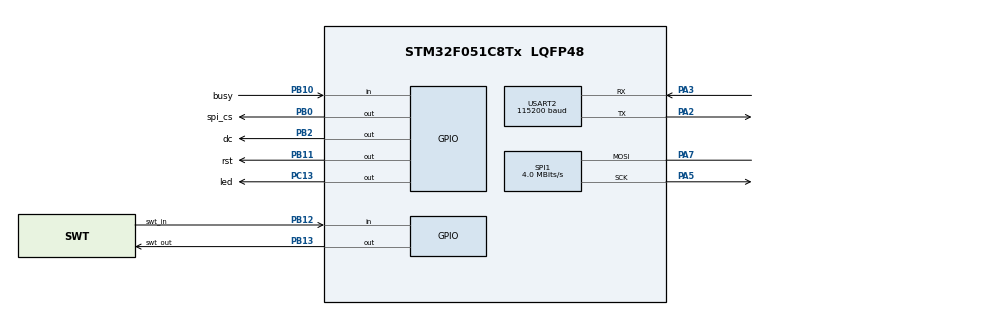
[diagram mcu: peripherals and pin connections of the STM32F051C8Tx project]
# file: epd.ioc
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Mcu.Family=STM32F0
Mcu.Name=STM32F051C8Tx
Mcu.Package=LQFP48
NVIC.RTC_IRQn=true\:0\:0\:false\:false\:true\:true
NVIC.USART2_IRQn=true\:0\:0\:false\:false\:true\:true
PA13.Mode=Serial_Wire
PA13.Signal=SYS_SWDIO
PA14.Mode=Serial_Wire
PA14.Signal=SYS_SWCLK
PA2.Mode=Asynchronous
PA2.Signal=USART2_TX
PA3.Mode=Asynchronous
PA3.Signal=USART2_RX
PA5.Mode=Simplex_Bidirectional_Master
PA5.Signal=SPI1_SCK
PA7.Mode=Simplex_Bidirectional_Master
PA7.Signal=SPI1_MOSI
PB0.GPIO_Label=spi_cs
PB0.Signal=GPIO_Output
PB10.GPIO_Label=busy
PB10.Signal=GPIO_Input
PB11.GPIO_Label=rst
PB11.Signal=GPIO_Output
PB12.GPIO_Label=swt_in
PB12.Signal=GPIO_Input
PB13.GPIO_Label=swt_out
PB13.Signal=GPIO_Output
PB2.GPIO_Label=dc
PB2.Signal=GPIO_Output
PC13.GPIO_Label=led
PC13.Signal=GPIO_Output
PC14-OSC32_IN.Mode=LSE-External-Oscillator
PC14-OSC32_IN.Signal=RCC_OSC32_IN
PC15-OSC32_OUT.Mode=LSE-External-Oscillator
PC15-OSC32_OUT.Signal=RCC_OSC32_OUT
PF0-OSC_IN.Mode=HSE-External-Oscillator
PF0-OSC_IN.Signal=RCC_OSC_IN
PF1-OSC_OUT.Mode=HSE-External-Oscillator
PF1-OSC_OUT.Signal=RCC_OSC_OUT
ProjectManager.HeapSize=0x200
ProjectManager.StackSize=0x400
ProjectManager.TargetToolchain=Makefile
RCC.AHBFreq_Value=16000000
RCC.APB1Freq_Value=16000000
RCC.APB1TimFreq_Value=16000000
RCC.HCLKFreq_Value=16000000
RCC.PLLSourceVirtual=RCC_PLLSOURCE_HSE
RCC.RTCClockSelection=RCC_RTCCLKSOURCE_LSE
RCC.SYSCLKFreq_VALUE=16000000
RCC.SYSCLKSource=RCC_SYSCLKSOURCE_PLLCLK
RTC.Alarm-Alarm\ A=RTC_ALARM_A
RTC.AlarmMaskDateWeekDay-Alarm\ A=RTC_ALARMMASK_DATEWEEKDAY
RTC.AlarmMaskHours-Alarm\ A=RTC_ALARMMASK_HOURS
RTC.AlarmMaskMinutes-Alarm\ A=RTC_ALARMMASK_MINUTES
RTC.AlarmSubSecondMask-Alarm\ A=RTC_ALARMSUBSECONDMASK_ALL
SPI1.BaudRatePrescaler=SPI_BAUDRATEPRESCALER_4
SPI1.CalculateBaudRate=4.0 MBits/s
SPI1.DataSize=SPI_DATASIZE_8BIT
SPI1.Direction=SPI_DIRECTION_1LINE
SPI1.Mode=SPI_MODE_MASTER
SPI1.VirtualType=VM_MASTER
USART2.BaudRate=115200
USART2.VirtualMode-Asynchronous=VM_ASYNC
VP_RTC_VS_RTC_Activate.Mode=RTC_Enabled
VP_RTC_VS_RTC_Alarm_A_Intern.Mode=Alarm A
VP_RTC_VS_RTC_Calendar.Mode=RTC_Calendar
board=epd

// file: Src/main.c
/**
  ******************************************************************************
  * @file           : main.c
  * @brief          : Main program body
  ******************************************************************************
  ** This notice applies to any and all portions of this file
  * that are not between comment pairs USER CODE BEGIN and
  * USER CODE END. Other portions of this file, whether
  * inserted by the user or by software development tools
  * are owned by their respective copyright owners.
  *
  * COPYRIGHT(c) 2018 STMicroelectronics
  *
  * Redistribution and use in source and binary forms, with or without modification,
  * are permitted provided that the following conditions are met:
  *   1. Redistributions of source code must retain the above copyright notice,
  *      this list of conditions and the following disclaimer.
  *   2. Redistributions in binary form must reproduce the above copyright notice,
  *      this list of conditions and the following disclaimer in the documentation
  *      and/or other materials provided with the distribution.
  *   3. Neither the name of STMicroelectronics nor the names of its contributors
  *      may be used to endorse or promote products derived from this software
  *      without specific prior written permission.
  *
  * THIS SOFTWARE IS PROVIDED BY THE COPYRIGHT HOLDERS AND CONTRIBUTORS "AS IS"
  * AND ANY EXPRESS OR IMPLIED WARRANTIES, INCLUDING, BUT NOT LIMITED TO, THE
  * IMPLIED WARRANTIES OF MERCHANTABILITY AND FITNESS FOR A PARTICULAR PURPOSE ARE
  * DISCLAIMED. IN NO EVENT SHALL THE COPYRIGHT HOLDER OR CONTRIBUTORS BE LIABLE
  * FOR ANY DIRECT, INDIRECT, INCIDENTAL, SPECIAL, EXEMPLARY, OR CONSEQUENTIAL
  * DAMAGES (INCLUDING, BUT NOT LIMITED TO, PROCUREMENT OF SUBSTITUTE GOODS OR
  * SERVICES; LOSS OF USE, DATA, OR PROFITS; OR BUSINESS INTERRUPTION) HOWEVER
  * CAUSED AND ON ANY THEORY OF LIABILITY, WHETHER IN CONTRACT, STRICT LIABILITY,
  * OR TORT (INCLUDING NEGLIGENCE OR OTHERWISE) ARISING IN ANY WAY OUT OF THE USE
  * OF THIS SOFTWARE, EVEN IF ADVISED OF THE POSSIBILITY OF SUCH DAMAGE.
  *
  ******************************************************************************
  */
#include "main.h"
#include "stm32f0xx_hal.h"

/* USER CODE BEGIN Includes */
#include "epd2in9.h"
#include "epdif.h"
#include "epdpaint.h"
#include "bitmaps.h"
#include <stdlib.h>

/* USER CODE END Includes */

RTC_HandleTypeDef hrtc;

SPI_HandleTypeDef hspi1;

UART_HandleTypeDef huart2;

/* USER CODE BEGIN PV */
/* Private variables ---------------------------------------------------------*/
#define COLORED      0
#define UNCOLORED    1
/* After this many RTC-alarm wakeups without any UART activity, fall back
   from SLEEP (UART debug) mode to the low-power STOP mode. */
#define UART_IDLE_TIMEOUT_MIN  5

int uart_state = 0;
uint8_t rxBuf[12];
uint32_t uart_idle_min = 0;         /* consecutive alarm wakeups w/o UART traffic */
volatile uint8_t rtc_alarm_flag = 0; /* set in HAL_RTC_AlarmAEventCallback */

/* USER CODE END PV */

void SystemClock_Config(void);
static void MX_GPIO_Init(void);
static void MX_RTC_Init(void);
static void MX_SPI1_Init(void);
static void MX_USART2_UART_Init(void);
static void MY_GPIO_DeInit(void);

/* USER CODE BEGIN PFP */
/* Private function prototypes -----------------------------------------------*/

/* USER CODE END PFP */

/* USER CODE BEGIN 0 */
void HAL_UART_RxCpltCallback(UART_HandleTypeDef *UartHandle)
{
    uart_idle_min = 0;   /* any UART traffic resets the idle timeout */
    /* Zero-initialize: HAL_RTC_SetTime() ORs DayLightSaving/StoreOperation
       into RTC->CR, so stack garbage here could set CR.FMT (12-hour mode),
       disable Alarm A, or trigger a DST hour shift. */
    RTC_TimeTypeDef st = {0};
    RTC_DateTypeDef sd = {0};
    switch (uart_state) {
        case 0:
            HAL_UART_Transmit_IT(UartHandle, (uint8_t *)"\r\nInput Date(yy-mm-dd:w):\r\n", 27);
            HAL_UART_Receive_IT(UartHandle, rxBuf, 10);
            uart_state = 1;
            break;
        case 1:
            sd.Year = (rxBuf[0] - '0') * 10 + rxBuf[1] - '0';
            sd.Month = (rxBuf[3] - '0') * 10 + rxBuf[4] - '0';
            sd.Date = (rxBuf[6] - '0') * 10 + rxBuf[7] - '0';
            sd.WeekDay = rxBuf[9] - '0';
            HAL_RTC_SetDate(&hrtc, &sd, RTC_FORMAT_BIN);
            HAL_UART_Transmit_IT(UartHandle, (uint8_t *)"\r\nInput Time(hh:mm:ss):\r\n", 25);
            HAL_UART_Receive_IT(UartHandle, rxBuf, 8);
            uart_state = 2;
            break;
        case 2:
            st.Hours = (rxBuf[0] - '0') * 10 + rxBuf[1] - '0';
            st.Minutes = (rxBuf[3] - '0') * 10 + rxBuf[4] - '0';
            st.Seconds = (rxBuf[6] - '0') * 10 + rxBuf[7] - '0';
            st.TimeFormat = RTC_HOURFORMAT_24;
            /* USE_FULL_ASSERT is off, so the HAL would silently write an
               invalid hour (e.g. 15 into a 12-hour-mode RTC) and let the
               hour counter run past 23.  Validate before writing. */
            if ((st.Hours > 23) || (st.Minutes > 59) || (st.Seconds > 59)) {
                HAL_UART_Transmit_IT(UartHandle, (uint8_t *)"\r\nBad Time, Input Again(hh:mm:ss):\r\n", 34);
                HAL_UART_Receive_IT(UartHandle, rxBuf, 8);
                break;   /* stay in state 2 and retry */
            }
            if (HAL_RTC_SetTime(&hrtc, &st, RTC_FORMAT_BIN) != HAL_OK) {
                HAL_UART_Transmit_IT(UartHandle, (uint8_t *)"\r\nRTC Set Time Failed!\r\n", 24);
                HAL_UART_Receive_IT(UartHandle, rxBuf, 1);
                uart_state = 3;
                break;
            }
            HAL_UART_Transmit_IT(UartHandle, (uint8_t *)"\r\nInput Done!\r\n", 15);
            HAL_UART_Receive_IT(UartHandle, rxBuf, 1);
            uart_state = 3;
            break;
    }

}

void HAL_RTC_AlarmAEventCallback(RTC_HandleTypeDef *hrtc)
{
    rtc_alarm_flag = 1;  /* remember that the RTC alarm woke the MCU */
//    HAL_GPIO_TogglePin(led_GPIO_Port, led_Pin);
}
/* USER CODE END 0 */

int main(void)
{
  /* USER CODE BEGIN 1 */
  unsigned char* frame_buffer = (unsigned char*)malloc(EPD_WIDTH * EPD_HEIGHT / 8);

  /* USER CODE END 1 */

  /* MCU Configuration----------------------------------------------------------*/

  /* Reset of all peripherals, Initializes the Flash interface and the Systick. */
  HAL_Init();

  /* Configure the system clock */
  SystemClock_Config();

  /* Initialize all configured peripherals */
  MX_GPIO_Init();
  MX_RTC_Init();
  MX_SPI1_Init();
  MX_USART2_UART_Init();
  /* USER CODE BEGIN 2 */
  EPD epd;
  if (EPD_Init(&epd, lut_full_update) != 0) {
    printf("e-Paper init failed\n");
    return -1;
  }

  Paint paint;
  Paint_Init(&paint, frame_buffer, epd.width, epd.height);
  Paint_Clear(&paint, UNCOLORED);
  Paint_SetRotate(&paint, ROTATE_90);

  Paint_DrawStringAt(&paint, 20, 50, "Simple Calendar.", &Font24, COLORED);
  EPD_SetFrameMemory(&epd, frame_buffer, 0, 0, Paint_GetWidth(&paint), Paint_GetHeight(&paint));
  EPD_DisplayFrame(&epd);

  Paint_Clear(&paint, UNCOLORED);

  /* USER CODE END 2 */

  /* Infinite loop */
  /* USER CODE BEGIN WHILE */
  HAL_GPIO_WritePin(led_GPIO_Port, led_Pin, GPIO_PIN_SET);
  int swton = 1;
  HAL_GPIO_WritePin(swt_out_GPIO_Port, swt_out_Pin, GPIO_PIN_SET);
  if (HAL_GPIO_ReadPin(swt_in_GPIO_Port, swt_in_Pin) != GPIO_PIN_SET) swton = 0;
  HAL_GPIO_WritePin(swt_out_GPIO_Port, swt_out_Pin, GPIO_PIN_RESET);
  if (HAL_GPIO_ReadPin(swt_in_GPIO_Port, swt_in_Pin) != GPIO_PIN_RESET) swton = 0;
  if (swton)
      HAL_UART_Receive_IT(&huart2, rxBuf, 1);
  else {
      MY_GPIO_DeInit();
  }
  while (1)
  {
      RTC_TimeTypeDef st;
      RTC_DateTypeDef sd;
      char date[10];
      const char* wkd[] = {"Mon", "Tue", "Wen", "Thu", "Fri", "Sat", "Sun"};

      /* Read the RTC current time first.  After every low-power wakeup the
         calendar shadow registers must be re-synchronized with the APB clock
         domain (clear RSF, wait until it is set again) before reading, or the
         read can return torn values; the HAL documents this as mandatory
         after wakeup from low-power modes. */
      if (HAL_RTC_WaitForSynchro(&hrtc) != HAL_OK) {
        printf("RTC sync failed\n");
      }
      HAL_RTC_GetTime(&hrtc, &st, RTC_FORMAT_BIN);
      HAL_RTC_GetDate(&hrtc, &sd, RTC_FORMAT_BIN);

      /* Once a day (00:00) do a full refresh to clear partial-update
         ghosting, as required by the vendor after many partial refreshes.
         The old approach reset the MCU at exactly 00:00:00; that collided
         with the calendar's day rollover and could corrupt the hour field
         (hours kept counting past 23 while the date never advanced).  A
         plain full refresh here never touches the RTC at the rollover
         instant, so the calendar cannot be disturbed. */
      int full_refresh = (st.Hours == 0) && (st.Minutes == 0);

      /* Wake the e-Paper from deep sleep (EPD_Sleep is called at the end of
         the previous loop iteration). Deep sleep keeps its standby current
         near zero, but a full re-init is required before the next refresh. */
      if (EPD_Init(&epd, full_refresh ? lut_full_update : lut_partial_update) != 0) {
        printf("e-Paper init failed\n");
        return -1;
      }

      /* Write strings to the buffer */
      HAL_GPIO_WritePin(led_GPIO_Port, led_Pin, GPIO_PIN_RESET);
      Paint_DrawFilledRectangle(&paint, 50, 0, 290, 24, UNCOLORED);
      Paint_DrawFilledRectangle(&paint, 0, 120, 296, 127, UNCOLORED);
      sprintf(date, "%02d-%02d-%02d", sd.Year, sd.Month, sd.Date);
      Paint_DrawStringAt(&paint, 50, 0, date, &Font24, COLORED);
      Paint_DrawStringAt(&paint, 200, 0, wkd[sd.WeekDay - 1], &Font24, COLORED);
      Paint_DrawBitmap(&paint, 0, 28, 9, 85, digits[st.Hours / 10]);
      Paint_DrawBitmap(&paint, 70, 28, 9, 85, digits[st.Hours % 10]);
      Paint_DrawBitmap(&paint, 10 + 70 * 2, 28, 9, 85, digits[st.Minutes / 10]);
      Paint_DrawBitmap(&paint, 10 + 70 * 3, 28, 9, 85, digits[st.Minutes % 10]);
      Paint_DrawBitmap(&paint, 135, 55, 2, 13, point);
      Paint_DrawBitmap(&paint, 135, 85, 2, 13, point);
      HAL_GPIO_WritePin(led_GPIO_Port, led_Pin, GPIO_PIN_SET);
      /* Display the frame_buffer (single refresh; the duplicated one was
         removed to halve the refresh energy) */
      EPD_SetFrameMemory(&epd, frame_buffer, 0, 0, Paint_GetWidth(&paint), Paint_GetHeight(&paint));
      EPD_DisplayFrame(&epd);
      /* Deep sleep the e-Paper to cut its standby current */
      EPD_Sleep(&epd);

      if (swton) {
          /* UART/time-setting mode: count RTC-alarm wakeups. If no UART
             traffic arrives for UART_IDLE_TIMEOUT_MIN minutes, switch to
             STOP mode (lowest MCU idle current). */
          if (rtc_alarm_flag) {
              rtc_alarm_flag = 0;
              if (++uart_idle_min >= UART_IDLE_TIMEOUT_MIN) {
                  swton = 0;
                  MY_GPIO_DeInit();
              }
          }
          HAL_SuspendTick();
          HAL_PWR_EnterSLEEPMode(PWR_MAINREGULATOR_ON, PWR_SLEEPENTRY_WFI);
          HAL_ResumeTick();
      } else {
          HAL_PWR_EnterSTOPMode(PWR_LOWPOWERREGULATOR_ON, PWR_STOPENTRY_WFI);
          SystemClock_Config();
      }

  /* USER CODE END WHILE */

  }

}

void SystemClock_Config(void)
{

  RCC_OscInitTypeDef RCC_OscInitStruct;
  RCC_ClkInitTypeDef RCC_ClkInitStruct;
  RCC_PeriphCLKInitTypeDef PeriphClkInit;

    /**Configure LSE Drive Capability
    */
  HAL_PWR_EnableBkUpAccess();

  __HAL_RCC_LSEDRIVE_CONFIG(RCC_LSEDRIVE_LOW);

    /**Initializes the CPU, AHB and APB busses clocks
    * Runs on 8MHz HSI without HSE/PLL: halves the MCU active current
    * (the HSE crystal and PLL are not needed by any peripheral).
    */
  RCC_OscInitStruct.OscillatorType = RCC_OSCILLATORTYPE_HSI|RCC_OSCILLATORTYPE_LSE;
  RCC_OscInitStruct.HSIState = RCC_HSI_ON;
  RCC_OscInitStruct.HSICalibrationValue = RCC_HSICALIBRATION_DEFAULT;
  RCC_OscInitStruct.LSEState = RCC_LSE_ON;
  if (HAL_RCC_OscConfig(&RCC_OscInitStruct) != HAL_OK)
  {
    _Error_Handler(__FILE__, __LINE__);
  }

    /**Initializes the CPU, AHB and APB busses clocks
    */
  RCC_ClkInitStruct.ClockType = RCC_CLOCKTYPE_HCLK|RCC_CLOCKTYPE_SYSCLK
                              |RCC_CLOCKTYPE_PCLK1;
  RCC_ClkInitStruct.SYSCLKSource = RCC_SYSCLKSOURCE_HSI;
  RCC_ClkInitStruct.AHBCLKDivider = RCC_SYSCLK_DIV1;
  RCC_ClkInitStruct.APB1CLKDivider = RCC_HCLK_DIV1;

  if (HAL_RCC_ClockConfig(&RCC_ClkInitStruct, FLASH_LATENCY_0) != HAL_OK)
  {
    _Error_Handler(__FILE__, __LINE__);
  }

  PeriphClkInit.PeriphClockSelection = RCC_PERIPHCLK_RTC;
  PeriphClkInit.RTCClockSelection = RCC_RTCCLKSOURCE_LSE;
  if (HAL_RCCEx_PeriphCLKConfig(&PeriphClkInit) != HAL_OK)
  {
    _Error_Handler(__FILE__, __LINE__);
  }

    /**Configure the Systick interrupt time
    */
  HAL_SYSTICK_Config(HAL_RCC_GetHCLKFreq()/1000);

    /**Configure the Systick
    */
  HAL_SYSTICK_CLKSourceConfig(SYSTICK_CLKSOURCE_HCLK);

  /* SysTick_IRQn interrupt configuration */
  HAL_NVIC_SetPriority(SysTick_IRQn, 0, 0);
}

/* RTC init function */
static void MX_RTC_Init(void)
{

//  RTC_TimeTypeDef sTime;
//  RTC_DateTypeDef sDate;
  RTC_AlarmTypeDef sAlarm = {0};  /* zero-init: AlarmSubSecondMask must not be stack garbage */

    /**Initialize RTC Only
    */
  hrtc.Instance = RTC;
  hrtc.Init.HourFormat = RTC_HOURFORMAT_24;
  hrtc.Init.AsynchPrediv = 127;
  hrtc.Init.SynchPrediv = 255;
  hrtc.Init.OutPut = RTC_OUTPUT_DISABLE;
  hrtc.Init.OutPutPolarity = RTC_OUTPUT_POLARITY_HIGH;
  hrtc.Init.OutPutType = RTC_OUTPUT_TYPE_OPENDRAIN;
  if (HAL_RTC_Init(&hrtc) != HAL_OK)
  {
    _Error_Handler(__FILE__, __LINE__);
  }

    /**Initialize RTC and set the Time and Date
    *
  sTime.Hours = 0x0;
  sTime.Minutes = 0x0;
  sTime.Seconds = 0x0;
  sTime.DayLightSaving = RTC_DAYLIGHTSAVING_NONE;
  sTime.StoreOperation = RTC_STOREOPERATION_RESET;
  if (HAL_RTC_SetTime(&hrtc, &sTime, RTC_FORMAT_BCD) != HAL_OK)
  {
    _Error_Handler(__FILE__, __LINE__);
  }

  sDate.WeekDay = RTC_WEEKDAY_MONDAY;
  sDate.Month = RTC_MONTH_JANUARY;
  sDate.Date = 0x1;
  sDate.Year = 0x0;

  if (HAL_RTC_SetDate(&hrtc, &sDate, RTC_FORMAT_BCD) != HAL_OK)
  {
    _Error_Handler(__FILE__, __LINE__);
  }

    *Enable the Alarm A
    */
  sAlarm.AlarmTime.Hours = 0x0;
  sAlarm.AlarmTime.Minutes = 0x0;
  sAlarm.AlarmTime.Seconds = 0x0;
  sAlarm.AlarmTime.SubSeconds = 0x0;
  sAlarm.AlarmTime.DayLightSaving = RTC_DAYLIGHTSAVING_NONE;
  sAlarm.AlarmTime.StoreOperation = RTC_STOREOPERATION_RESET;
  /* Wake every minute: only seconds are compared (must equal 0); date,
     weekday, hours and minutes are all masked off. */
  sAlarm.AlarmMask = RTC_ALARMMASK_DATEWEEKDAY|RTC_ALARMMASK_HOURS
                              |RTC_ALARMMASK_MINUTES;
  /* Sub-seconds must not participate in the match either. */
  sAlarm.AlarmSubSecondMask = RTC_ALARMSUBSECONDMASK_ALL;
  sAlarm.AlarmDateWeekDaySel = RTC_ALARMDATEWEEKDAYSEL_DATE;
  sAlarm.AlarmDateWeekDay = 0x1;
  sAlarm.Alarm = RTC_ALARM_A;
  if (HAL_RTC_SetAlarm_IT(&hrtc, &sAlarm, RTC_FORMAT_BIN) != HAL_OK)
  {
    _Error_Handler(__FILE__, __LINE__);
  }

  HAL_RTCEx_BKUPWrite(&hrtc,RTC_BKP_DR0,0x32F2);

}

/* SPI1 init function */
static void MX_SPI1_Init(void)
{

  /* SPI1 parameter configuration*/
  hspi1.Instance = SPI1;
  hspi1.Init.Mode = SPI_MODE_MASTER;
  hspi1.Init.Direction = SPI_DIRECTION_1LINE;
  hspi1.Init.DataSize = SPI_DATASIZE_8BIT;
  hspi1.Init.CLKPolarity = SPI_POLARITY_LOW;
  hspi1.Init.CLKPhase = SPI_PHASE_1EDGE;
  hspi1.Init.NSS = SPI_NSS_SOFT;
  hspi1.Init.BaudRatePrescaler = SPI_BAUDRATEPRESCALER_4;
  hspi1.Init.FirstBit = SPI_FIRSTBIT_MSB;
  hspi1.Init.TIMode = SPI_TIMODE_DISABLE;
  hspi1.Init.CRCCalculation = SPI_CRCCALCULATION_DISABLE;
  hspi1.Init.CRCPolynomial = 7;
  hspi1.Init.CRCLength = SPI_CRC_LENGTH_DATASIZE;
  hspi1.Init.NSSPMode = SPI_NSS_PULSE_ENABLE;
  if (HAL_SPI_Init(&hspi1) != HAL_OK)
  {
    _Error_Handler(__FILE__, __LINE__);
  }

}

/* USART2 init function */
static void MX_USART2_UART_Init(void)
{

  huart2.Instance = USART2;
  huart2.Init.BaudRate = 115200;
  huart2.Init.WordLength = UART_WORDLENGTH_8B;
  huart2.Init.StopBits = UART_STOPBITS_1;
  huart2.Init.Parity = UART_PARITY_NONE;
  huart2.Init.Mode = UART_MODE_TX_RX;
  huart2.Init.HwFlowCtl = UART_HWCONTROL_NONE;
  huart2.Init.OverSampling = UART_OVERSAMPLING_16;
  huart2.Init.OneBitSampling = UART_ONE_BIT_SAMPLE_DISABLE;
  huart2.AdvancedInit.AdvFeatureInit = UART_ADVFEATURE_NO_INIT;
  if (HAL_UART_Init(&huart2) != HAL_OK)
  {
    _Error_Handler(__FILE__, __LINE__);
  }

}

/** Configure pins as
        * Analog
        * Input
        * Output
        * EVENT_OUT
        * EXTI
        * Free pins are configured automatically as Analog (this feature is enabled through
        * the Code Generation settings)
*/

static void MY_GPIO_DeInit(void)
{
  HAL_GPIO_DeInit(GPIOB, swt_in_Pin);
  HAL_UART_MspDeInit(&huart2);
}

static void MX_GPIO_Init(void)
{

  GPIO_InitTypeDef GPIO_InitStruct;

  /* GPIO Ports Clock Enable */
  __HAL_RCC_GPIOC_CLK_ENABLE();
  __HAL_RCC_GPIOF_CLK_ENABLE();
  __HAL_RCC_GPIOA_CLK_ENABLE();
  __HAL_RCC_GPIOB_CLK_ENABLE();

  /*Configure GPIO pin Output Level */
  HAL_GPIO_WritePin(led_GPIO_Port, led_Pin, GPIO_PIN_RESET);

  /*Configure GPIO pin Output Level */
  HAL_GPIO_WritePin(GPIOB, spi_cs_Pin|dc_Pin|rst_Pin|swt_out_Pin, GPIO_PIN_RESET);

  /*Configure GPIO pin : led_Pin */
  GPIO_InitStruct.Pin = led_Pin;
  GPIO_InitStruct.Mode = GPIO_MODE_OUTPUT_PP;
  GPIO_InitStruct.Pull = GPIO_NOPULL;
  GPIO_InitStruct.Speed = GPIO_SPEED_FREQ_LOW;
  HAL_GPIO_Init(led_GPIO_Port, &GPIO_InitStruct);

  /*Configure GPIO pins : PA0 PA1 PA4 PA6
                           PA8 PA9 PA10 PA11
                           PA12 PA15 */
  GPIO_InitStruct.Pin = GPIO_PIN_0|GPIO_PIN_1|GPIO_PIN_4|GPIO_PIN_6
                          |GPIO_PIN_8|GPIO_PIN_9|GPIO_PIN_10|GPIO_PIN_11
                          |GPIO_PIN_12|GPIO_PIN_15;
  GPIO_InitStruct.Mode = GPIO_MODE_ANALOG;
  GPIO_InitStruct.Pull = GPIO_NOPULL;
  HAL_GPIO_Init(GPIOA, &GPIO_InitStruct);

  /*Configure GPIO pins : spi_cs_Pin dc_Pin rst_Pin swt_out_Pin */
  GPIO_InitStruct.Pin = spi_cs_Pin|dc_Pin|rst_Pin|swt_out_Pin;
  GPIO_InitStruct.Mode = GPIO_MODE_OUTPUT_PP;
  GPIO_InitStruct.Pull = GPIO_NOPULL;
  GPIO_InitStruct.Speed = GPIO_SPEED_FREQ_LOW;
  HAL_GPIO_Init(GPIOB, &GPIO_InitStruct);

  /*Configure GPIO pins : PB1 PB14 PB15 PB3
                           PB4 PB5 PB6 PB7
                           PB8 PB9 */
  GPIO_InitStruct.Pin = GPIO_PIN_1|GPIO_PIN_14|GPIO_PIN_15|GPIO_PIN_3
                          |GPIO_PIN_4|GPIO_PIN_5|GPIO_PIN_6|GPIO_PIN_7
                          |GPIO_PIN_8|GPIO_PIN_9;
  GPIO_InitStruct.Mode = GPIO_MODE_ANALOG;
  GPIO_InitStruct.Pull = GPIO_NOPULL;
  HAL_GPIO_Init(GPIOB, &GPIO_InitStruct);

  /*Configure GPIO pin : busy_Pin */
  GPIO_InitStruct.Pin = busy_Pin;
  GPIO_InitStruct.Mode = GPIO_MODE_INPUT;
  GPIO_InitStruct.Pull = GPIO_NOPULL;
  HAL_GPIO_Init(GPIOB, &GPIO_InitStruct);

  /*Configure GPIO pin : swt_in_Pin (pull-down so an open switch reads LOW
    and the device defaults to battery/STOP mode instead of floating) */
  GPIO_InitStruct.Pin = swt_in_Pin;
  GPIO_InitStruct.Mode = GPIO_MODE_INPUT;
  GPIO_InitStruct.Pull = GPIO_PULLDOWN;
  HAL_GPIO_Init(GPIOB, &GPIO_InitStruct);

  /*Configure GPIO pins : PF6 PF7 */
  GPIO_InitStruct.Pin = GPIO_PIN_6|GPIO_PIN_7;
  GPIO_InitStruct.Mode = GPIO_MODE_ANALOG;
  GPIO_InitStruct.Pull = GPIO_NOPULL;
  HAL_GPIO_Init(GPIOF, &GPIO_InitStruct);

}

void _Error_Handler(char *file, int line)
{
  while(1)
  {
  }
}

/************************ (C) COPYRIGHT STMicroelectronics *****END OF FILE****/
